VERSION 5.7 ;
  NOWIREEXTENSIONATPIN ON ;
  DIVIDERCHAR "/" ;
  BUSBITCHARS "[]" ;
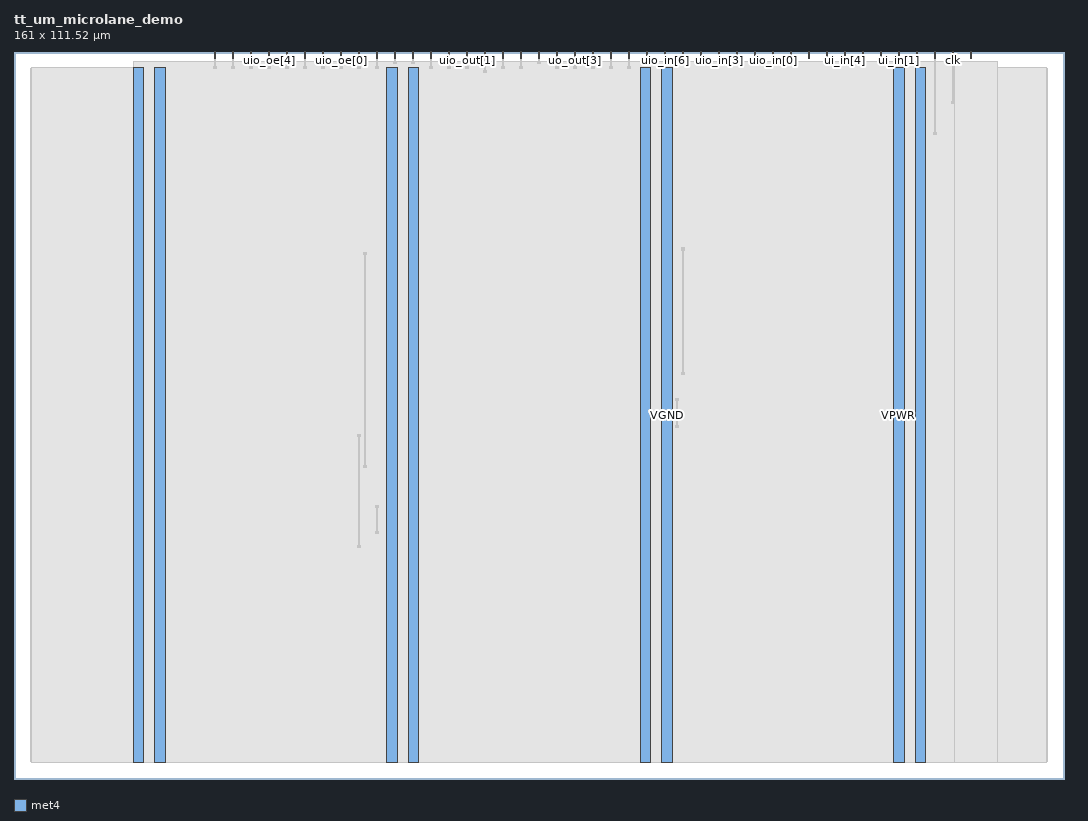
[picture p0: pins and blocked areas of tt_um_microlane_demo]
MACRO tt_um_microlane_demo
  CLASS BLOCK ;
  FOREIGN tt_um_microlane_demo ;
  ORIGIN 0.000 0.000 ;
  SIZE 161.000 BY 111.520 ;
  PIN VPWR
    DIRECTION INOUT ;
    USE POWER ;
    PORT
      LAYER met4 ;
        RECT 18.280 2.480 19.880 109.040 ;
    END
    PORT
      LAYER met4 ;
        RECT 57.150 2.480 58.750 109.040 ;
    END
    PORT
      LAYER met4 ;
        RECT 96.020 2.480 97.620 109.040 ;
    END
    PORT
      LAYER met4 ;
        RECT 134.890 2.480 136.490 109.040 ;
    END
  END VPWR
  PIN VGND
    DIRECTION INOUT ;
    USE GROUND ;
    PORT
      LAYER met4 ;
        RECT 21.580 2.480 23.180 109.040 ;
    END
    PORT
      LAYER met4 ;
        RECT 60.450 2.480 62.050 109.040 ;
    END
    PORT
      LAYER met4 ;
        RECT 99.320 2.480 100.920 109.040 ;
    END
    PORT
      LAYER met4 ;
        RECT 138.190 2.480 139.790 109.040 ;
    END
  END VGND
  PIN ena
    DIRECTION INPUT ;
    USE SIGNAL ;
    PORT
      LAYER met4 ;
        RECT 146.590 110.520 146.890 111.520 ;
    END
  END ena
  PIN clk
    DIRECTION INPUT ;
    USE SIGNAL ;
    PORT
      LAYER met4 ;
        RECT 143.830 110.520 144.130 111.520 ;
    END
  END clk
  PIN rst_n
    DIRECTION INPUT ;
    USE SIGNAL ;
    PORT
      LAYER met4 ;
        RECT 141.070 110.520 141.370 111.520 ;
    END
  END rst_n
  PIN ui_in[0]
    DIRECTION INPUT ;
    USE SIGNAL ;
    PORT
      LAYER met4 ;
        RECT 138.310 110.520 138.610 111.520 ;
    END
  END ui_in[0]
  PIN ui_in[1]
    DIRECTION INPUT ;
    USE SIGNAL ;
    PORT
      LAYER met4 ;
        RECT 135.550 110.520 135.850 111.520 ;
    END
  END ui_in[1]
  PIN ui_in[2]
    DIRECTION INPUT ;
    USE SIGNAL ;
    PORT
      LAYER met4 ;
        RECT 132.790 110.520 133.090 111.520 ;
    END
  END ui_in[2]
  PIN ui_in[3]
    DIRECTION INPUT ;
    USE SIGNAL ;
    PORT
      LAYER met4 ;
        RECT 130.030 110.520 130.330 111.520 ;
    END
  END ui_in[3]
  PIN ui_in[4]
    DIRECTION INPUT ;
    USE SIGNAL ;
    PORT
      LAYER met4 ;
        RECT 127.270 110.520 127.570 111.520 ;
    END
  END ui_in[4]
  PIN ui_in[5]
    DIRECTION INPUT ;
    USE SIGNAL ;
    PORT
      LAYER met4 ;
        RECT 124.510 110.520 124.810 111.520 ;
    END
  END ui_in[5]
  PIN ui_in[6]
    DIRECTION INPUT ;
    USE SIGNAL ;
    PORT
      LAYER met4 ;
        RECT 121.750 110.520 122.050 111.520 ;
    END
  END ui_in[6]
  PIN ui_in[7]
    DIRECTION INPUT ;
    USE SIGNAL ;
    PORT
      LAYER met4 ;
        RECT 118.990 110.520 119.290 111.520 ;
    END
  END ui_in[7]
  PIN uio_in[0]
    DIRECTION INPUT ;
    USE SIGNAL ;
    PORT
      LAYER met4 ;
        RECT 116.230 110.520 116.530 111.520 ;
    END
  END uio_in[0]
  PIN uio_in[1]
    DIRECTION INPUT ;
    USE SIGNAL ;
    PORT
      LAYER met4 ;
        RECT 113.470 110.520 113.770 111.520 ;
    END
  END uio_in[1]
  PIN uio_in[2]
    DIRECTION INPUT ;
    USE SIGNAL ;
    PORT
      LAYER met4 ;
        RECT 110.710 110.520 111.010 111.520 ;
    END
  END uio_in[2]
  PIN uio_in[3]
    DIRECTION INPUT ;
    USE SIGNAL ;
    PORT
      LAYER met4 ;
        RECT 107.950 110.520 108.250 111.520 ;
    END
  END uio_in[3]
  PIN uio_in[4]
    DIRECTION INPUT ;
    USE SIGNAL ;
    PORT
      LAYER met4 ;
        RECT 105.190 110.520 105.490 111.520 ;
    END
  END uio_in[4]
  PIN uio_in[5]
    DIRECTION INPUT ;
    USE SIGNAL ;
    PORT
      LAYER met4 ;
        RECT 102.430 110.520 102.730 111.520 ;
    END
  END uio_in[5]
  PIN uio_in[6]
    DIRECTION INPUT ;
    USE SIGNAL ;
    PORT
      LAYER met4 ;
        RECT 99.670 110.520 99.970 111.520 ;
    END
  END uio_in[6]
  PIN uio_in[7]
    DIRECTION INPUT ;
    USE SIGNAL ;
    PORT
      LAYER met4 ;
        RECT 96.910 110.520 97.210 111.520 ;
    END
  END uio_in[7]
  PIN uo_out[0]
    DIRECTION OUTPUT ;
    USE SIGNAL ;
    PORT
      LAYER met4 ;
        RECT 94.150 110.520 94.450 111.520 ;
    END
  END uo_out[0]
  PIN uo_out[1]
    DIRECTION OUTPUT ;
    USE SIGNAL ;
    PORT
      LAYER met4 ;
        RECT 91.390 110.520 91.690 111.520 ;
    END
  END uo_out[1]
  PIN uo_out[2]
    DIRECTION OUTPUT ;
    USE SIGNAL ;
    PORT
      LAYER met4 ;
        RECT 88.630 110.520 88.930 111.520 ;
    END
  END uo_out[2]
  PIN uo_out[3]
    DIRECTION OUTPUT ;
    USE SIGNAL ;
    PORT
      LAYER met4 ;
        RECT 85.870 110.520 86.170 111.520 ;
    END
  END uo_out[3]
  PIN uo_out[4]
    DIRECTION OUTPUT ;
    USE SIGNAL ;
    PORT
      LAYER met4 ;
        RECT 83.110 110.520 83.410 111.520 ;
    END
  END uo_out[4]
  PIN uo_out[5]
    DIRECTION OUTPUT ;
    USE SIGNAL ;
    PORT
      LAYER met4 ;
        RECT 80.350 110.520 80.650 111.520 ;
    END
  END uo_out[5]
  PIN uo_out[6]
    DIRECTION OUTPUT ;
    USE SIGNAL ;
    PORT
      LAYER met4 ;
        RECT 77.590 110.520 77.890 111.520 ;
    END
  END uo_out[6]
  PIN uo_out[7]
    DIRECTION OUTPUT ;
    USE SIGNAL ;
    PORT
      LAYER met4 ;
        RECT 74.830 110.520 75.130 111.520 ;
    END
  END uo_out[7]
  PIN uio_out[0]
    DIRECTION OUTPUT ;
    USE SIGNAL ;
    PORT
      LAYER met4 ;
        RECT 72.070 110.520 72.370 111.520 ;
    END
  END uio_out[0]
  PIN uio_out[1]
    DIRECTION OUTPUT ;
    USE SIGNAL ;
    PORT
      LAYER met4 ;
        RECT 69.310 110.520 69.610 111.520 ;
    END
  END uio_out[1]
  PIN uio_out[2]
    DIRECTION OUTPUT ;
    USE SIGNAL ;
    PORT
      LAYER met4 ;
        RECT 66.550 110.520 66.850 111.520 ;
    END
  END uio_out[2]
  PIN uio_out[3]
    DIRECTION OUTPUT ;
    USE SIGNAL ;
    PORT
      LAYER met4 ;
        RECT 63.790 110.520 64.090 111.520 ;
    END
  END uio_out[3]
  PIN uio_out[4]
    DIRECTION OUTPUT ;
    USE SIGNAL ;
    PORT
      LAYER met4 ;
        RECT 61.030 110.520 61.330 111.520 ;
    END
  END uio_out[4]
  PIN uio_out[5]
    DIRECTION OUTPUT ;
    USE SIGNAL ;
    PORT
      LAYER met4 ;
        RECT 58.270 110.520 58.570 111.520 ;
    END
  END uio_out[5]
  PIN uio_out[6]
    DIRECTION OUTPUT ;
    USE SIGNAL ;
    PORT
      LAYER met4 ;
        RECT 55.510 110.520 55.810 111.520 ;
    END
  END uio_out[6]
  PIN uio_out[7]
    DIRECTION OUTPUT ;
    USE SIGNAL ;
    PORT
      LAYER met4 ;
        RECT 52.750 110.520 53.050 111.520 ;
    END
  END uio_out[7]
  PIN uio_oe[0]
    DIRECTION OUTPUT ;
    USE SIGNAL ;
    PORT
      LAYER met4 ;
        RECT 49.990 110.520 50.290 111.520 ;
    END
  END uio_oe[0]
  PIN uio_oe[1]
    DIRECTION OUTPUT ;
    USE SIGNAL ;
    PORT
      LAYER met4 ;
        RECT 47.230 110.520 47.530 111.520 ;
    END
  END uio_oe[1]
  PIN uio_oe[2]
    DIRECTION OUTPUT ;
    USE SIGNAL ;
    PORT
      LAYER met4 ;
        RECT 44.470 110.520 44.770 111.520 ;
    END
  END uio_oe[2]
  PIN uio_oe[3]
    DIRECTION OUTPUT ;
    USE SIGNAL ;
    PORT
      LAYER met4 ;
        RECT 41.710 110.520 42.010 111.520 ;
    END
  END uio_oe[3]
  PIN uio_oe[4]
    DIRECTION OUTPUT ;
    USE SIGNAL ;
    PORT
      LAYER met4 ;
        RECT 38.950 110.520 39.250 111.520 ;
    END
  END uio_oe[4]
  PIN uio_oe[5]
    DIRECTION OUTPUT ;
    USE SIGNAL ;
    PORT
      LAYER met4 ;
        RECT 36.190 110.520 36.490 111.520 ;
    END
  END uio_oe[5]
  PIN uio_oe[6]
    DIRECTION OUTPUT ;
    USE SIGNAL ;
    PORT
      LAYER met4 ;
        RECT 33.430 110.520 33.730 111.520 ;
    END
  END uio_oe[6]
  PIN uio_oe[7]
    DIRECTION OUTPUT ;
    USE SIGNAL ;
    PORT
      LAYER met4 ;
        RECT 30.670 110.520 30.970 111.520 ;
    END
  END uio_oe[7]
  OBS
      LAYER nwell ;
        RECT 2.570 2.635 158.430 108.990 ;
      LAYER li1 ;
        RECT 2.760 2.635 158.240 108.885 ;
      LAYER met1 ;
        RECT 2.760 2.480 158.240 109.040 ;
      LAYER met2 ;
        RECT 18.310 2.535 150.780 110.005 ;
      LAYER met3 ;
        RECT 18.290 2.555 144.170 110.015 ;
      LAYER met4 ;
        RECT 18.280 2.480 19.880 109.040 ;
        RECT 57.150 2.480 58.750 109.040 ;
        RECT 96.020 2.480 97.620 109.040 ;
        RECT 134.890 2.480 136.490 109.040 ;
        RECT 21.580 2.480 23.180 109.040 ;
        RECT 60.450 2.480 62.050 109.040 ;
        RECT 99.320 2.480 100.920 109.040 ;
        RECT 138.190 2.480 139.790 109.040 ;
        RECT 146.590 110.520 146.890 111.520 ;
        RECT 143.830 110.520 144.130 111.520 ;
        RECT 141.070 110.520 141.370 111.520 ;
        RECT 138.310 110.520 138.610 111.520 ;
        RECT 135.550 110.520 135.850 111.520 ;
        RECT 132.790 110.520 133.090 111.520 ;
        RECT 130.030 110.520 130.330 111.520 ;
        RECT 127.270 110.520 127.570 111.520 ;
        RECT 124.510 110.520 124.810 111.520 ;
        RECT 121.750 110.520 122.050 111.520 ;
        RECT 118.990 110.520 119.290 111.520 ;
        RECT 116.230 110.520 116.530 111.520 ;
        RECT 113.470 110.520 113.770 111.520 ;
        RECT 110.710 110.520 111.010 111.520 ;
        RECT 107.950 110.520 108.250 111.520 ;
        RECT 105.190 110.520 105.490 111.520 ;
        RECT 102.430 110.520 102.730 111.520 ;
        RECT 99.670 110.520 99.970 111.520 ;
        RECT 96.910 110.520 97.210 111.520 ;
        RECT 94.150 110.520 94.450 111.520 ;
        RECT 91.390 110.520 91.690 111.520 ;
        RECT 88.630 110.520 88.930 111.520 ;
        RECT 85.870 110.520 86.170 111.520 ;
        RECT 83.110 110.520 83.410 111.520 ;
        RECT 80.350 110.520 80.650 111.520 ;
        RECT 77.590 110.520 77.890 111.520 ;
        RECT 74.830 110.520 75.130 111.520 ;
        RECT 72.070 110.520 72.370 111.520 ;
        RECT 69.310 110.520 69.610 111.520 ;
        RECT 66.550 110.520 66.850 111.520 ;
        RECT 63.790 110.520 64.090 111.520 ;
        RECT 61.030 110.520 61.330 111.520 ;
        RECT 58.270 110.520 58.570 111.520 ;
        RECT 55.510 110.520 55.810 111.520 ;
        RECT 52.750 110.520 53.050 111.520 ;
        RECT 49.990 110.520 50.290 111.520 ;
        RECT 47.230 110.520 47.530 111.520 ;
        RECT 44.470 110.520 44.770 111.520 ;
        RECT 41.710 110.520 42.010 111.520 ;
        RECT 38.950 110.520 39.250 111.520 ;
        RECT 36.190 110.520 36.490 111.520 ;
        RECT 33.430 110.520 33.730 111.520 ;
        RECT 30.670 110.520 30.970 111.520 ;
        RECT 55.495 41.655 55.825 41.985 ;
        RECT 55.495 37.575 55.825 37.905 ;
        RECT 55.510 37.590 55.810 38.330 ;
        RECT 55.510 38.030 55.810 41.090 ;
        RECT 55.510 40.790 55.810 41.970 ;
        RECT 52.735 52.535 53.065 52.865 ;
        RECT 52.735 35.535 53.065 35.865 ;
        RECT 52.750 35.550 53.050 36.490 ;
        RECT 52.750 36.190 53.050 52.130 ;
        RECT 52.750 51.830 53.050 52.850 ;
        RECT 101.495 53.895 101.825 54.225 ;
        RECT 101.495 57.975 101.825 58.305 ;
        RECT 101.510 53.910 101.810 54.890 ;
        RECT 101.510 54.590 101.810 57.650 ;
        RECT 101.510 57.350 101.810 58.290 ;
        RECT 53.655 80.415 53.985 80.745 ;
        RECT 53.655 47.775 53.985 48.105 ;
        RECT 53.670 47.790 53.970 48.450 ;
        RECT 53.670 48.150 53.970 80.650 ;
        RECT 53.670 80.350 53.970 80.730 ;
        RECT 102.415 81.095 102.745 81.425 ;
        RECT 102.415 62.055 102.745 62.385 ;
        RECT 102.430 62.070 102.730 63.170 ;
        RECT 102.430 62.870 102.730 80.650 ;
        RECT 102.430 80.350 102.730 81.410 ;
        RECT 143.815 103.535 144.145 103.865 ;
        RECT 143.830 103.550 144.130 104.570 ;
        RECT 143.830 104.270 144.130 111.010 ;
        RECT 143.830 110.710 144.130 111.010 ;
        RECT 141.055 98.775 141.385 99.105 ;
        RECT 141.070 98.790 141.370 99.970 ;
        RECT 141.070 99.670 141.370 111.010 ;
        RECT 141.070 110.710 141.370 111.010 ;
        RECT 49.990 109.790 50.290 111.010 ;
        RECT 49.975 108.975 50.305 109.305 ;
        RECT 49.990 108.990 50.290 110.090 ;
        RECT 49.990 110.710 50.290 111.010 ;
        RECT 47.230 109.790 47.530 111.010 ;
        RECT 47.215 108.975 47.545 109.305 ;
        RECT 47.230 108.990 47.530 110.090 ;
        RECT 47.230 110.710 47.530 111.010 ;
        RECT 44.470 109.790 44.770 111.010 ;
        RECT 44.455 108.975 44.785 109.305 ;
        RECT 44.470 108.990 44.770 110.090 ;
        RECT 44.470 110.710 44.770 111.010 ;
        RECT 41.710 109.790 42.010 111.010 ;
        RECT 41.695 108.975 42.025 109.305 ;
        RECT 41.710 108.990 42.010 110.090 ;
        RECT 41.710 110.710 42.010 111.010 ;
        RECT 38.950 109.790 39.250 111.010 ;
        RECT 38.935 108.975 39.265 109.305 ;
        RECT 38.950 108.990 39.250 110.090 ;
        RECT 38.950 110.710 39.250 111.010 ;
        RECT 36.190 109.790 36.490 111.010 ;
        RECT 36.175 108.975 36.505 109.305 ;
        RECT 36.190 108.990 36.490 110.090 ;
        RECT 36.190 110.710 36.490 111.010 ;
        RECT 33.430 109.790 33.730 111.010 ;
        RECT 33.415 108.975 33.745 109.305 ;
        RECT 33.430 108.990 33.730 110.090 ;
        RECT 33.430 110.710 33.730 111.010 ;
        RECT 30.670 109.790 30.970 111.010 ;
        RECT 30.655 108.975 30.985 109.305 ;
        RECT 30.670 108.990 30.970 110.090 ;
        RECT 30.670 110.710 30.970 111.010 ;
        RECT 72.070 108.870 72.370 111.010 ;
        RECT 72.055 108.295 72.385 108.625 ;
        RECT 72.070 108.310 72.370 109.170 ;
        RECT 72.070 110.710 72.370 111.010 ;
        RECT 69.310 109.790 69.610 111.010 ;
        RECT 69.295 108.975 69.625 109.305 ;
        RECT 69.310 108.990 69.610 110.090 ;
        RECT 69.310 110.710 69.610 111.010 ;
        RECT 66.550 109.790 66.850 111.010 ;
        RECT 66.535 108.975 66.865 109.305 ;
        RECT 66.550 108.990 66.850 110.090 ;
        RECT 66.550 110.710 66.850 111.010 ;
        RECT 63.790 109.790 64.090 111.010 ;
        RECT 63.775 108.975 64.105 109.305 ;
        RECT 63.790 108.990 64.090 110.090 ;
        RECT 63.790 110.710 64.090 111.010 ;
        RECT 61.030 109.790 61.330 111.010 ;
        RECT 61.015 109.655 61.345 109.985 ;
        RECT 61.030 109.670 61.330 110.090 ;
        RECT 61.030 110.710 61.330 111.010 ;
        RECT 58.270 109.790 58.570 111.010 ;
        RECT 58.255 109.655 58.585 109.985 ;
        RECT 58.270 109.670 58.570 110.090 ;
        RECT 58.270 110.710 58.570 111.010 ;
        RECT 55.510 109.790 55.810 111.010 ;
        RECT 55.495 108.975 55.825 109.305 ;
        RECT 55.510 108.990 55.810 110.090 ;
        RECT 55.510 110.710 55.810 111.010 ;
        RECT 52.750 109.790 53.050 111.010 ;
        RECT 52.735 108.975 53.065 109.305 ;
        RECT 52.750 108.990 53.050 110.090 ;
        RECT 52.750 110.710 53.050 111.010 ;
        RECT 94.150 109.790 94.450 111.010 ;
        RECT 94.135 108.975 94.465 109.305 ;
        RECT 94.150 108.990 94.450 110.090 ;
        RECT 94.150 110.710 94.450 111.010 ;
        RECT 91.390 109.790 91.690 111.010 ;
        RECT 91.375 108.975 91.705 109.305 ;
        RECT 91.390 108.990 91.690 110.090 ;
        RECT 91.390 110.710 91.690 111.010 ;
        RECT 88.630 109.790 88.930 111.010 ;
        RECT 88.615 108.975 88.945 109.305 ;
        RECT 88.630 108.990 88.930 110.090 ;
        RECT 88.630 110.710 88.930 111.010 ;
        RECT 85.870 109.790 86.170 111.010 ;
        RECT 85.855 108.975 86.185 109.305 ;
        RECT 85.870 108.990 86.170 110.090 ;
        RECT 85.870 110.710 86.170 111.010 ;
        RECT 83.110 109.790 83.410 111.010 ;
        RECT 83.095 108.975 83.425 109.305 ;
        RECT 83.110 108.990 83.410 110.090 ;
        RECT 83.110 110.710 83.410 111.010 ;
        RECT 80.350 109.790 80.650 111.010 ;
        RECT 80.335 109.655 80.665 109.985 ;
        RECT 80.350 109.670 80.650 110.090 ;
        RECT 80.350 110.710 80.650 111.010 ;
        RECT 77.590 109.790 77.890 111.010 ;
        RECT 77.575 108.975 77.905 109.305 ;
        RECT 77.590 108.990 77.890 110.090 ;
        RECT 77.590 110.710 77.890 111.010 ;
        RECT 74.830 109.790 75.130 111.010 ;
        RECT 74.815 108.975 75.145 109.305 ;
        RECT 74.830 108.990 75.130 110.090 ;
        RECT 74.830 110.710 75.130 111.010 ;
  END
END tt_um_microlane_demo
END LIBRARY

